VERSION 5.8 ;
BUSBITCHARS "[]" ;
DIVIDERCHAR "/" ;
UNITS
    DATABASE MICRONS 1000 ;
END UNITS

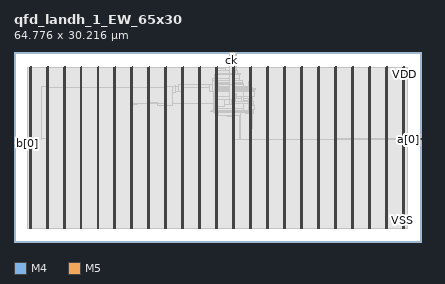
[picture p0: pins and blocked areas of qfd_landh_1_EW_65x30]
MACRO qfd_landh_1_EW_65x30
  FOREIGN qfd_landh_1_EW_65x30 0 0 ;
  CLASS BLOCK ;
  SIZE 64.776 BY 30.216 ;
  PIN a[0]
    DIRECTION INPUT ;
    USE SIGNAL ;
    PORT
      LAYER M4 ;
        RECT  64.692 16.272 64.776 16.296 ;
    END
  END a[0]
  PIN b[0]
    DIRECTION OUTPUT ;
    USE SIGNAL ;
    PORT
      LAYER M4 ;
        RECT  0 15.696 0.084 15.72 ;
    END
  END b[0]
  PIN ck
    DIRECTION INPUT ;
    USE SIGNAL ;
    PORT
      LAYER M5 ;
        RECT  34.512 30.132 34.536 30.216 ;
    END
  END ck
  PIN ckf
    DIRECTION INPUT ;
    USE SIGNAL ;
    PORT
      LAYER M5 ;
        RECT  34.608 30.132 34.632 30.216 ;
    END
  END ckf
  PIN ea
    DIRECTION INPUT ;
    USE SIGNAL ;
    PORT
      LAYER M4 ;
        RECT  64.692 16.368 64.776 16.392 ;
    END
  END ea
  PIN fault
    DIRECTION OUTPUT ;
    USE SIGNAL ;
    PORT
      LAYER M5 ;
        RECT  34.704 30.132 34.728 30.216 ;
    END
  END fault
  PIN k0
    DIRECTION INPUT ;
    USE SIGNAL ;
    PORT
      LAYER M5 ;
        RECT  34.8 30.132 34.824 30.216 ;
    END
  END k0
  PIN k1
    DIRECTION INPUT ;
    USE SIGNAL ;
    PORT
      LAYER M5 ;
        RECT  34.896 30.132 34.92 30.216 ;
    END
  END k1
  PIN k2
    DIRECTION INPUT ;
    USE SIGNAL ;
    PORT
      LAYER M5 ;
        RECT  34.992 30.132 35.016 30.216 ;
    END
  END k2
  PIN rs
    DIRECTION INPUT ;
    USE SIGNAL ;
    PORT
      LAYER M5 ;
        RECT  35.088 30.132 35.112 30.216 ;
    END
  END rs
  PIN tie_hi
    DIRECTION OUTPUT ;
    USE SIGNAL ;
    PORT
      LAYER M5 ;
        RECT  35.184 30.132 35.208 30.216 ;
    END
  END tie_hi
  PIN tie_lo
    DIRECTION OUTPUT ;
    USE SIGNAL ;
    PORT
      LAYER M5 ;
        RECT  35.28 30.132 35.304 30.216 ;
    END
  END tie_lo
  PIN VDD
    DIRECTION INOUT ;
    USE POWER ;
    PORT
      LAYER M5 ;
        RECT  61.992 2.151 62.112 27.833 ;
        RECT  59.292 2.151 59.412 27.833 ;
        RECT  56.592 2.151 56.712 27.833 ;
        RECT  53.892 2.151 54.012 27.833 ;
        RECT  51.192 2.151 51.312 27.833 ;
        RECT  48.492 2.151 48.612 27.833 ;
        RECT  45.792 2.151 45.912 27.833 ;
        RECT  43.092 2.151 43.212 27.833 ;
        RECT  40.392 2.151 40.512 27.833 ;
        RECT  37.692 2.151 37.812 27.833 ;
        RECT  34.992 2.151 35.112 27.833 ;
        RECT  32.292 2.151 32.412 27.833 ;
        RECT  29.592 2.151 29.712 27.833 ;
        RECT  26.892 2.151 27.012 27.833 ;
        RECT  24.192 2.151 24.312 27.833 ;
        RECT  21.492 2.151 21.612 27.833 ;
        RECT  18.792 2.151 18.912 27.833 ;
        RECT  16.092 2.151 16.212 27.833 ;
        RECT  13.392 2.151 13.512 27.833 ;
        RECT  10.692 2.151 10.812 27.833 ;
        RECT  7.992 2.151 8.112 27.833 ;
        RECT  5.292 2.151 5.412 27.833 ;
        RECT  2.592 2.151 2.712 27.833 ;
    END
  END VDD
  PIN VSS
    DIRECTION INOUT ;
    USE GROUND ;
    PORT
      LAYER M5 ;
        RECT  61.8 2.137 61.92 27.819 ;
        RECT  59.1 2.137 59.22 27.819 ;
        RECT  56.4 2.137 56.52 27.819 ;
        RECT  53.7 2.137 53.82 27.819 ;
        RECT  51 2.137 51.12 27.819 ;
        RECT  48.3 2.137 48.42 27.819 ;
        RECT  45.6 2.137 45.72 27.819 ;
        RECT  42.9 2.137 43.02 27.819 ;
        RECT  40.2 2.137 40.32 27.819 ;
        RECT  37.5 2.137 37.62 27.819 ;
        RECT  34.8 2.137 34.92 27.819 ;
        RECT  32.1 2.137 32.22 27.819 ;
        RECT  29.4 2.137 29.52 27.819 ;
        RECT  26.7 2.137 26.82 27.819 ;
        RECT  24 2.137 24.12 27.819 ;
        RECT  21.3 2.137 21.42 27.819 ;
        RECT  18.6 2.137 18.72 27.819 ;
        RECT  15.9 2.137 16.02 27.819 ;
        RECT  13.2 2.137 13.32 27.819 ;
        RECT  10.5 2.137 10.62 27.819 ;
        RECT  7.8 2.137 7.92 27.819 ;
        RECT  5.1 2.137 5.22 27.819 ;
        RECT  2.4 2.137 2.52 27.819 ;
    END
  END VSS
  OBS
    LAYER RVTN ;
     RECT  2.16 2.16 62.586 2.295 ;
     RECT  2.16 2.565 62.586 2.835 ;
     RECT  2.16 3.105 62.586 3.375 ;
     RECT  2.16 3.645 62.586 3.915 ;
     RECT  2.16 4.185 62.586 4.455 ;
     RECT  2.16 4.725 62.586 4.995 ;
     RECT  2.16 5.265 62.586 5.535 ;
     RECT  2.16 5.805 62.586 6.075 ;
     RECT  2.16 6.345 62.586 6.615 ;
     RECT  2.16 6.885 62.586 7.155 ;
     RECT  2.16 7.425 62.586 7.695 ;
     RECT  2.16 7.965 62.586 8.235 ;
     RECT  2.16 8.505 62.586 8.775 ;
     RECT  2.16 9.045 62.586 9.315 ;
     RECT  2.16 9.585 62.586 9.855 ;
     RECT  2.16 10.125 62.586 10.395 ;
     RECT  2.16 10.665 62.586 10.935 ;
     RECT  2.16 11.205 62.586 11.475 ;
     RECT  2.16 11.745 62.586 12.015 ;
     RECT  2.16 12.285 62.586 12.555 ;
     RECT  2.16 12.825 62.586 13.095 ;
     RECT  2.16 13.365 62.586 13.635 ;
     RECT  2.16 13.905 62.586 14.175 ;
     RECT  2.16 14.445 62.586 14.715 ;
     RECT  2.16 14.985 62.586 15.255 ;
     RECT  2.16 15.525 62.586 15.795 ;
     RECT  2.16 16.065 62.586 16.335 ;
     RECT  2.16 16.605 62.586 16.875 ;
     RECT  2.16 17.145 62.586 17.415 ;
     RECT  2.16 17.685 62.586 17.955 ;
     RECT  2.16 18.225 62.586 18.495 ;
     RECT  2.16 18.765 62.586 19.035 ;
     RECT  2.16 19.305 62.586 19.575 ;
     RECT  2.16 19.845 62.586 20.115 ;
     RECT  2.16 20.385 62.586 20.655 ;
     RECT  2.16 20.925 62.586 21.195 ;
     RECT  2.16 21.465 62.586 21.735 ;
     RECT  2.16 22.005 62.586 22.275 ;
     RECT  2.16 22.545 62.586 22.815 ;
     RECT  2.16 23.085 62.586 23.355 ;
     RECT  2.16 23.625 62.586 23.895 ;
     RECT  2.16 24.165 62.586 24.435 ;
     RECT  2.16 24.705 62.586 24.975 ;
     RECT  2.16 25.245 62.586 25.515 ;
     RECT  2.16 25.785 62.586 26.055 ;
     RECT  2.16 26.325 62.586 26.595 ;
     RECT  2.16 26.865 62.586 27.135 ;
     RECT  2.16 27.405 62.586 27.675 ;
    LAYER RVTP ;
     RECT  2.16 2.295 62.586 2.565 ;
     RECT  2.16 2.835 62.586 3.105 ;
     RECT  2.16 3.375 62.586 3.645 ;
     RECT  2.16 3.915 62.586 4.185 ;
     RECT  2.16 4.455 62.586 4.725 ;
     RECT  2.16 4.995 62.586 5.265 ;
     RECT  2.16 5.535 62.586 5.805 ;
     RECT  2.16 6.075 62.586 6.345 ;
     RECT  2.16 6.615 62.586 6.885 ;
     RECT  2.16 7.155 62.586 7.425 ;
     RECT  2.16 7.695 62.586 7.965 ;
     RECT  2.16 8.235 62.586 8.505 ;
     RECT  2.16 8.775 62.586 9.045 ;
     RECT  2.16 9.315 62.586 9.585 ;
     RECT  2.16 9.855 62.586 10.125 ;
     RECT  2.16 10.395 62.586 10.665 ;
     RECT  2.16 10.935 62.586 11.205 ;
     RECT  2.16 11.475 62.586 11.745 ;
     RECT  2.16 12.015 62.586 12.285 ;
     RECT  2.16 12.555 62.586 12.825 ;
     RECT  2.16 13.095 62.586 13.365 ;
     RECT  2.16 13.635 62.586 13.905 ;
     RECT  2.16 14.175 62.586 14.445 ;
     RECT  2.16 14.715 62.586 14.985 ;
     RECT  2.16 15.255 62.586 15.525 ;
     RECT  2.16 15.795 62.586 16.065 ;
     RECT  2.16 16.335 62.586 16.605 ;
     RECT  2.16 16.875 62.586 17.145 ;
     RECT  2.16 17.415 62.586 17.685 ;
     RECT  2.16 17.955 62.586 18.225 ;
     RECT  2.16 18.495 62.586 18.765 ;
     RECT  2.16 19.035 62.586 19.305 ;
     RECT  2.16 19.575 62.586 19.845 ;
     RECT  2.16 20.115 62.586 20.385 ;
     RECT  2.16 20.655 62.586 20.925 ;
     RECT  2.16 21.195 62.586 21.465 ;
     RECT  2.16 21.735 62.586 22.005 ;
     RECT  2.16 22.275 62.586 22.545 ;
     RECT  2.16 22.815 62.586 23.085 ;
     RECT  2.16 23.355 62.586 23.625 ;
     RECT  2.16 23.895 62.586 24.165 ;
     RECT  2.16 24.435 62.586 24.705 ;
     RECT  2.16 24.975 62.586 25.245 ;
     RECT  2.16 25.515 62.586 25.785 ;
     RECT  2.16 26.055 62.586 26.325 ;
     RECT  2.16 26.595 62.586 26.865 ;
     RECT  2.16 27.135 62.586 27.405 ;
     RECT  2.16 27.675 62.586 27.81 ;
    LAYER M1 ;
     RECT  2.16 2.151 62.586 27.819 ;
    LAYER M2 ;
     RECT  2.16 2.151 62.586 27.819 ;
    LAYER M3 ;
     RECT  2.415 2.143 2.505 2.413 ;
     RECT  5.115 2.143 5.205 2.413 ;
     RECT  7.815 2.143 7.905 2.413 ;
     RECT  10.515 2.143 10.605 2.413 ;
     RECT  13.215 2.143 13.305 2.413 ;
     RECT  15.915 2.143 16.005 2.413 ;
     RECT  18.615 2.143 18.705 2.413 ;
     RECT  21.315 2.143 21.405 2.413 ;
     RECT  24.015 2.143 24.105 2.413 ;
     RECT  26.715 2.143 26.805 2.413 ;
     RECT  29.415 2.143 29.505 2.413 ;
     RECT  32.115 2.143 32.205 2.413 ;
     RECT  34.815 2.143 34.905 2.413 ;
     RECT  37.515 2.143 37.605 2.413 ;
     RECT  40.215 2.143 40.305 2.413 ;
     RECT  42.915 2.143 43.005 2.413 ;
     RECT  45.615 2.143 45.705 2.413 ;
     RECT  48.315 2.143 48.405 2.413 ;
     RECT  51.015 2.143 51.105 2.413 ;
     RECT  53.715 2.143 53.805 2.413 ;
     RECT  56.415 2.143 56.505 2.413 ;
     RECT  59.115 2.143 59.205 2.413 ;
     RECT  61.815 2.143 61.905 2.413 ;
     RECT  2.415 2.413 2.697 15.787 ;
     RECT  0.108 15.691 0.126 15.821 ;
     RECT  2.415 15.787 3.15 15.899 ;
     RECT  51.015 2.413 51.297 16.363 ;
     RECT  4.356 16.375 4.374 16.411 ;
     RECT  5.115 2.413 5.397 16.411 ;
     RECT  4.356 16.411 5.397 16.541 ;
     RECT  37.515 2.413 37.797 18.121 ;
     RECT  51.015 16.363 51.354 18.185 ;
     RECT  34.815 2.413 35.097 20.005 ;
     RECT  34.416 20.005 35.097 20.011 ;
     RECT  37.515 18.121 37.89 20.011 ;
     RECT  32.115 2.413 32.397 20.119 ;
     RECT  32.115 20.119 33.102 20.191 ;
     RECT  34.02 20.011 35.097 20.191 ;
     RECT  35.928 16.267 35.946 20.191 ;
     RECT  37.404 20.011 37.89 20.461 ;
     RECT  32.115 20.191 36.018 20.659 ;
     RECT  36.864 20.461 38.07 20.659 ;
     RECT  31.716 20.659 38.07 20.683 ;
     RECT  31.248 20.683 38.07 20.723 ;
     RECT  31.392 20.723 38.07 20.731 ;
     RECT  31.392 20.731 38.142 20.849 ;
     RECT  31.68 20.849 36.594 20.957 ;
     RECT  37.404 20.849 38.142 21.127 ;
     RECT  31.68 20.957 36.522 21.263 ;
     RECT  37.404 21.127 38.178 21.659 ;
     RECT  18.615 2.413 18.897 21.901 ;
     RECT  37.404 21.659 38.07 21.931 ;
     RECT  18.615 21.901 19.602 22.013 ;
     RECT  31.716 21.263 36.522 22.081 ;
     RECT  37.332 21.931 38.07 22.081 ;
     RECT  22.824 21.739 22.842 22.157 ;
     RECT  31.716 22.081 38.07 22.343 ;
     RECT  4.5 16.541 5.397 22.379 ;
     RECT  31.716 22.343 37.89 23.161 ;
     RECT  25.668 23.803 25.686 23.855 ;
     RECT  31.716 23.161 38.214 23.899 ;
     RECT  31.356 23.899 38.214 23.935 ;
     RECT  26.715 2.413 26.997 23.971 ;
     RECT  31.14 23.935 38.214 23.981 ;
     RECT  31.356 23.981 38.214 24.089 ;
     RECT  26.208 23.971 26.997 24.125 ;
     RECT  31.896 24.089 38.214 24.241 ;
     RECT  31.896 24.241 38.358 24.359 ;
     RECT  31.896 24.359 37.89 24.503 ;
     RECT  25.092 24.619 25.686 24.665 ;
     RECT  31.896 24.503 37.797 24.737 ;
     RECT  25.668 24.665 25.686 24.809 ;
     RECT  31.896 24.737 36.522 25.007 ;
     RECT  31.896 25.007 36.486 25.169 ;
     RECT  31.896 25.169 36.378 25.249 ;
     RECT  31.68 25.249 36.378 25.313 ;
     RECT  37.26 24.737 37.797 25.475 ;
     RECT  31.68 25.313 36.342 25.675 ;
     RECT  31.644 25.675 36.342 25.709 ;
     RECT  31.644 25.709 35.91 25.979 ;
     RECT  32.115 25.979 35.91 26.671 ;
     RECT  32.115 26.671 36.054 26.789 ;
     RECT  32.115 26.789 35.622 26.825 ;
     RECT  32.115 26.825 35.514 27.329 ;
     RECT  2.415 15.899 2.697 27.557 ;
     RECT  5.115 22.379 5.397 27.557 ;
     RECT  7.815 2.413 8.097 27.557 ;
     RECT  10.515 2.413 10.797 27.557 ;
     RECT  13.215 2.413 13.497 27.557 ;
     RECT  15.915 2.413 16.197 27.557 ;
     RECT  18.615 22.013 18.897 27.557 ;
     RECT  21.315 2.413 21.597 27.557 ;
     RECT  24.015 2.413 24.297 27.557 ;
     RECT  26.715 24.125 26.997 27.557 ;
     RECT  29.415 2.413 29.697 27.557 ;
     RECT  32.115 27.329 33.57 27.557 ;
     RECT  37.515 25.475 37.797 27.557 ;
     RECT  40.215 2.413 40.497 27.557 ;
     RECT  42.915 2.413 43.197 27.557 ;
     RECT  45.615 2.413 45.897 27.557 ;
     RECT  48.315 2.413 48.597 27.557 ;
     RECT  51.015 18.185 51.297 27.557 ;
     RECT  53.715 2.413 53.997 27.557 ;
     RECT  56.415 2.413 56.697 27.557 ;
     RECT  59.115 2.413 59.397 27.557 ;
     RECT  61.815 2.413 62.097 27.557 ;
     RECT  32.307 27.557 33.57 27.599 ;
     RECT  33.12 27.599 33.57 27.671 ;
     RECT  33.552 27.671 33.57 27.707 ;
     RECT  2.607 27.557 2.697 27.827 ;
     RECT  5.307 27.557 5.397 27.827 ;
     RECT  8.007 27.557 8.097 27.827 ;
     RECT  10.707 27.557 10.797 27.827 ;
     RECT  13.407 27.557 13.497 27.827 ;
     RECT  16.107 27.557 16.197 27.827 ;
     RECT  18.807 27.557 18.897 27.827 ;
     RECT  21.507 27.557 21.597 27.827 ;
     RECT  24.207 27.557 24.297 27.827 ;
     RECT  26.907 27.557 26.997 27.827 ;
     RECT  29.607 27.557 29.697 27.827 ;
     RECT  32.307 27.599 32.397 27.827 ;
     RECT  37.707 27.557 37.797 27.827 ;
     RECT  40.407 27.557 40.497 27.827 ;
     RECT  43.107 27.557 43.197 27.827 ;
     RECT  45.807 27.557 45.897 27.827 ;
     RECT  48.507 27.557 48.597 27.827 ;
     RECT  51.207 27.557 51.297 27.827 ;
     RECT  53.907 27.557 53.997 27.827 ;
     RECT  56.607 27.557 56.697 27.827 ;
     RECT  59.307 27.557 59.397 27.827 ;
     RECT  62.007 27.557 62.097 27.827 ;
     RECT  34.704 27.329 35.334 29.693 ;
     RECT  35.136 29.693 35.334 29.933 ;
     RECT  35.136 29.933 35.226 30.029 ;
     RECT  35.136 30.029 35.154 30.077 ;
    LAYER M4 ;
     RECT  0.06 15.696 0.097 15.72 ;
     RECT  0.097 15.696 0.137 15.816 ;
     RECT  0.137 15.792 2.408 15.816 ;
     RECT  2.408 2.148 2.512 27.552 ;
     RECT  2.512 2.418 2.6 27.552 ;
     RECT  2.6 2.418 2.704 27.822 ;
     RECT  2.704 15.792 3.161 15.816 ;
     RECT  4.345 16.512 5.108 16.536 ;
     RECT  4.357 24.624 5.108 24.648 ;
     RECT  5.108 2.148 5.212 27.552 ;
     RECT  5.212 2.418 5.3 27.552 ;
     RECT  5.3 2.418 5.404 27.822 ;
     RECT  5.404 24.624 7.808 24.648 ;
     RECT  7.808 2.148 7.912 27.552 ;
     RECT  7.912 2.418 8 27.552 ;
     RECT  8 2.418 8.104 27.822 ;
     RECT  8.104 24.624 10.508 24.648 ;
     RECT  10.508 2.148 10.612 27.552 ;
     RECT  10.612 2.418 10.7 27.552 ;
     RECT  10.7 2.418 10.804 27.822 ;
     RECT  10.804 24.624 13.208 24.648 ;
     RECT  13.208 2.148 13.312 27.552 ;
     RECT  13.312 2.418 13.4 27.552 ;
     RECT  13.4 2.418 13.504 27.822 ;
     RECT  13.504 24.624 15.908 24.648 ;
     RECT  15.908 2.148 16.012 27.552 ;
     RECT  16.012 2.418 16.1 27.552 ;
     RECT  16.1 2.418 16.204 27.822 ;
     RECT  16.204 24.624 18.608 24.648 ;
     RECT  18.608 2.148 18.712 27.552 ;
     RECT  18.712 2.418 18.8 27.552 ;
     RECT  18.8 2.418 18.904 27.822 ;
     RECT  18.904 21.984 21.308 22.008 ;
     RECT  18.904 24.624 21.308 24.648 ;
     RECT  21.308 2.148 21.412 27.552 ;
     RECT  21.412 2.418 21.5 27.552 ;
     RECT  21.5 2.418 21.604 27.822 ;
     RECT  21.604 21.984 22.813 22.152 ;
     RECT  22.813 21.744 22.853 22.152 ;
     RECT  22.853 21.744 24.008 22.008 ;
     RECT  21.604 24.624 24.008 24.648 ;
     RECT  24.008 2.148 24.112 27.552 ;
     RECT  24.112 2.418 24.2 27.552 ;
     RECT  24.2 2.418 24.304 27.822 ;
     RECT  24.304 21.744 25.139 22.008 ;
     RECT  24.304 23.808 25.697 24.744 ;
     RECT  25.697 24 26.197 24.744 ;
     RECT  25.139 21.984 26.708 22.008 ;
     RECT  26.197 24 26.708 24.984 ;
     RECT  26.708 2.148 26.812 27.552 ;
     RECT  26.812 2.418 26.9 27.552 ;
     RECT  26.9 2.418 27.004 27.822 ;
     RECT  27.004 21.984 29.408 22.008 ;
     RECT  27.004 24.624 29.408 24.984 ;
     RECT  29.408 2.148 29.512 27.552 ;
     RECT  29.512 2.418 29.6 27.552 ;
     RECT  29.6 2.418 29.704 27.822 ;
     RECT  29.704 24.624 31.129 24.984 ;
     RECT  31.129 23.952 31.633 24.984 ;
     RECT  29.704 21.984 31.841 22.008 ;
     RECT  31.237 20.688 31.957 20.712 ;
     RECT  31.841 21.984 31.957 22.776 ;
     RECT  31.633 23.952 31.957 25.704 ;
     RECT  31.957 20.4 32.108 22.776 ;
     RECT  31.957 23.952 32.108 26.664 ;
     RECT  32.108 2.148 32.212 27.552 ;
     RECT  32.212 2.418 32.3 27.552 ;
     RECT  32.3 2.418 32.404 27.822 ;
     RECT  32.404 24 32.501 25.08 ;
     RECT  32.404 20.4 32.537 20.424 ;
     RECT  32.404 21.552 33.473 22.68 ;
     RECT  33.473 21.84 34.309 22.68 ;
     RECT  34.309 21.84 34.513 22.776 ;
     RECT  32.501 24 34.513 24.024 ;
     RECT  34.309 30.096 34.643 30.12 ;
     RECT  32.501 25.056 34.765 25.08 ;
     RECT  34.009 20.016 34.808 20.04 ;
     RECT  34.513 21.84 34.808 24.024 ;
     RECT  34.765 25.056 34.808 25.224 ;
     RECT  34.181 26.784 34.808 26.808 ;
     RECT  34.808 2.148 34.909 27.552 ;
     RECT  34.909 2.148 34.912 27.96 ;
     RECT  34.652 29.664 35.027 30.072 ;
     RECT  34.912 2.418 35.104 27.96 ;
     RECT  35.104 27.936 35.123 27.96 ;
     RECT  35.027 29.856 35.198 30.072 ;
     RECT  35.104 22.272 35.201 23.592 ;
     RECT  35.198 29.856 35.219 30.024 ;
     RECT  35.219 29.904 35.237 30.024 ;
     RECT  35.104 26.688 35.245 26.712 ;
     RECT  35.237 29.904 35.345 29.928 ;
     RECT  35.201 22.752 35.381 23.592 ;
     RECT  35.381 22.752 36.169 23.064 ;
     RECT  35.104 25.68 36.313 25.704 ;
     RECT  36.313 25.104 36.353 25.704 ;
     RECT  36.353 25.104 36.421 25.128 ;
     RECT  36.169 22.416 36.467 23.064 ;
     RECT  36.421 24.48 36.467 25.128 ;
     RECT  36.467 22.416 37.285 22.776 ;
     RECT  35.104 16.272 37.508 16.296 ;
     RECT  35.104 20.688 37.508 20.712 ;
     RECT  37.285 21.936 37.508 22.776 ;
     RECT  36.467 24.48 37.508 24.504 ;
     RECT  37.508 2.148 37.612 27.552 ;
     RECT  37.612 2.418 37.7 27.552 ;
     RECT  37.7 2.418 37.804 27.822 ;
     RECT  37.804 16.272 40.208 16.296 ;
     RECT  40.208 2.148 40.312 27.552 ;
     RECT  40.312 2.418 40.4 27.552 ;
     RECT  40.4 2.418 40.504 27.822 ;
     RECT  40.504 16.272 42.908 16.296 ;
     RECT  42.908 2.148 43.012 27.552 ;
     RECT  43.012 2.418 43.1 27.552 ;
     RECT  43.1 2.418 43.204 27.822 ;
     RECT  43.204 16.272 45.608 16.296 ;
     RECT  45.608 2.148 45.712 27.552 ;
     RECT  45.712 2.418 45.8 27.552 ;
     RECT  45.8 2.418 45.904 27.822 ;
     RECT  45.904 16.272 48.308 16.296 ;
     RECT  48.308 2.148 48.412 27.552 ;
     RECT  48.412 2.418 48.5 27.552 ;
     RECT  48.5 2.418 48.604 27.822 ;
     RECT  48.604 16.272 51.008 16.296 ;
     RECT  51.008 2.148 51.112 27.552 ;
     RECT  51.112 2.418 51.2 27.552 ;
     RECT  51.2 2.418 51.304 27.822 ;
     RECT  51.304 16.272 53.708 16.392 ;
     RECT  53.708 2.148 53.812 27.552 ;
     RECT  53.812 2.418 53.9 27.552 ;
     RECT  53.9 2.418 54.004 27.822 ;
     RECT  54.004 16.272 56.408 16.392 ;
     RECT  56.408 2.148 56.512 27.552 ;
     RECT  56.512 2.418 56.6 27.552 ;
     RECT  56.6 2.418 56.704 27.822 ;
     RECT  56.704 16.272 59.108 16.392 ;
     RECT  59.108 2.148 59.212 27.552 ;
     RECT  59.212 2.418 59.3 27.552 ;
     RECT  59.3 2.418 59.404 27.822 ;
     RECT  59.404 16.272 61.808 16.392 ;
     RECT  61.808 2.148 61.912 27.552 ;
     RECT  61.912 2.418 62 27.552 ;
     RECT  62 2.418 62.104 27.822 ;
     RECT  62.104 16.272 64.716 16.392 ;
    LAYER M5 ;
     RECT  2.4 2.137 2.52 2.151 ;
     RECT  5.1 2.137 5.22 2.151 ;
     RECT  7.8 2.137 7.92 2.151 ;
     RECT  10.5 2.137 10.62 2.151 ;
     RECT  13.2 2.137 13.32 2.151 ;
     RECT  15.9 2.137 16.02 2.151 ;
     RECT  18.6 2.137 18.72 2.151 ;
     RECT  21.3 2.137 21.42 2.151 ;
     RECT  24 2.137 24.12 2.151 ;
     RECT  26.7 2.137 26.82 2.151 ;
     RECT  29.4 2.137 29.52 2.151 ;
     RECT  32.1 2.137 32.22 2.151 ;
     RECT  34.8 2.137 34.92 2.151 ;
     RECT  37.5 2.137 37.62 2.151 ;
     RECT  40.2 2.137 40.32 2.151 ;
     RECT  42.9 2.137 43.02 2.151 ;
     RECT  45.6 2.137 45.72 2.151 ;
     RECT  48.3 2.137 48.42 2.151 ;
     RECT  51 2.137 51.12 2.151 ;
     RECT  53.7 2.137 53.82 2.151 ;
     RECT  56.4 2.137 56.52 2.151 ;
     RECT  59.1 2.137 59.22 2.151 ;
     RECT  61.8 2.137 61.92 2.151 ;
     RECT  5.1 2.151 5.412 16.501 ;
     RECT  32.1 2.151 32.412 20.389 ;
     RECT  37.5 2.151 37.812 20.677 ;
     RECT  31.968 20.389 32.412 21.395 ;
     RECT  24 2.151 24.312 21.733 ;
     RECT  34.8 2.151 35.112 21.973 ;
     RECT  37.296 20.677 37.812 22.405 ;
     RECT  36.432 22.405 37.812 22.451 ;
     RECT  32.1 21.395 32.412 22.741 ;
     RECT  34.512 21.973 35.112 22.741 ;
     RECT  26.7 2.151 27.012 23.989 ;
     RECT  4.368 16.501 5.412 24.659 ;
     RECT  24 21.733 25.128 24.659 ;
     RECT  24 24.659 24.984 24.755 ;
     RECT  26.208 23.989 27.012 24.995 ;
     RECT  34.32 22.741 35.112 25.045 ;
     RECT  36.432 22.451 36.456 25.139 ;
     RECT  31.872 22.741 32.412 25.715 ;
     RECT  31.968 25.715 32.412 26.675 ;
     RECT  34.224 25.045 35.112 26.677 ;
     RECT  34.224 26.677 35.208 26.819 ;
     RECT  2.4 2.151 2.712 27.819 ;
     RECT  5.1 24.659 5.412 27.819 ;
     RECT  7.8 2.151 8.112 27.819 ;
     RECT  10.5 2.151 10.812 27.819 ;
     RECT  13.2 2.151 13.512 27.819 ;
     RECT  15.9 2.151 16.212 27.819 ;
     RECT  18.6 2.151 18.912 27.819 ;
     RECT  21.3 2.151 21.612 27.819 ;
     RECT  24 24.755 24.312 27.819 ;
     RECT  26.7 24.995 27.012 27.819 ;
     RECT  29.4 2.151 29.712 27.819 ;
     RECT  32.1 26.675 32.412 27.819 ;
     RECT  37.5 22.451 37.812 27.819 ;
     RECT  40.2 2.151 40.512 27.819 ;
     RECT  42.9 2.151 43.212 27.819 ;
     RECT  45.6 2.151 45.912 27.819 ;
     RECT  48.3 2.151 48.612 27.819 ;
     RECT  51 2.151 51.312 27.819 ;
     RECT  53.7 2.151 54.012 27.819 ;
     RECT  56.4 2.151 56.712 27.819 ;
     RECT  59.1 2.151 59.412 27.819 ;
     RECT  61.8 2.151 62.112 27.819 ;
     RECT  2.592 27.819 2.712 27.833 ;
     RECT  5.292 27.819 5.412 27.833 ;
     RECT  7.992 27.819 8.112 27.833 ;
     RECT  10.692 27.819 10.812 27.833 ;
     RECT  13.392 27.819 13.512 27.833 ;
     RECT  16.092 27.819 16.212 27.833 ;
     RECT  18.792 27.819 18.912 27.833 ;
     RECT  21.492 27.819 21.612 27.833 ;
     RECT  24.192 27.819 24.312 27.833 ;
     RECT  26.892 27.819 27.012 27.833 ;
     RECT  29.592 27.819 29.712 27.833 ;
     RECT  32.292 27.819 32.412 27.833 ;
     RECT  37.692 27.819 37.812 27.833 ;
     RECT  40.392 27.819 40.512 27.833 ;
     RECT  43.092 27.819 43.212 27.833 ;
     RECT  45.792 27.819 45.912 27.833 ;
     RECT  48.492 27.819 48.612 27.833 ;
     RECT  51.192 27.819 51.312 27.833 ;
     RECT  53.892 27.819 54.012 27.833 ;
     RECT  56.592 27.819 56.712 27.833 ;
     RECT  59.292 27.819 59.412 27.833 ;
     RECT  61.992 27.819 62.112 27.833 ;
     RECT  34.32 26.819 35.208 29.893 ;
     RECT  34.32 29.893 35.304 30.131 ;
     RECT  34.512 30.131 35.304 30.16 ;
  END
END qfd_landh_1_EW_65x30
END LIBRARY
